VERSION 5.8 ;
BUSBITCHARS "[]" ;
DIVIDERCHAR "/" ;
UNITS DATABASE MICRONS 1000 ; END UNITS
MANUFACTURINGGRID 0.001 ;
LAYER M1 TYPE ROUTING ; DIRECTION HORIZONTAL ; PITCH 0.1 ; WIDTH 0.05 ; SPACING 0.05 ; END M1
SITE site CLASS CORE ; SIZE 1 BY 1 ; SYMMETRY Y ; END site
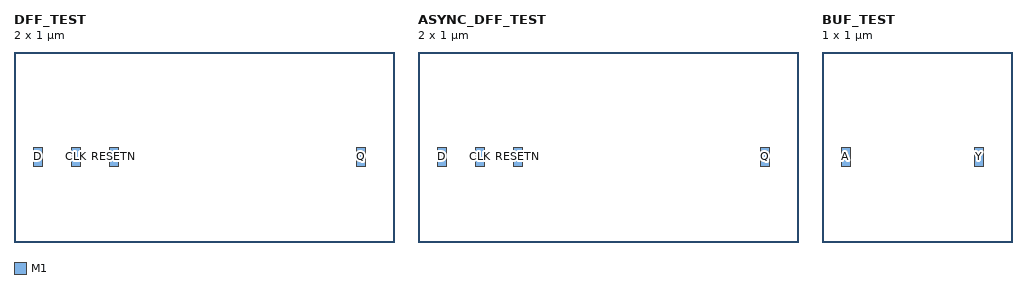
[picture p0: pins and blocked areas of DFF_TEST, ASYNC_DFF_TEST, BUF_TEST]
MACRO DFF_TEST CLASS CORE ; ORIGIN 0 0 ; SIZE 2 BY 1 ; SYMMETRY X Y ; SITE site ;
PIN D DIRECTION INPUT ; USE SIGNAL ; PORT LAYER M1 ; RECT 0.1 0.4 0.15000000000000002 0.5 ; END END D
PIN CLK DIRECTION INPUT ; USE SIGNAL ; PORT LAYER M1 ; RECT 0.3 0.4 0.35 0.5 ; END END CLK
PIN RESETN DIRECTION INPUT ; USE SIGNAL ; PORT LAYER M1 ; RECT 0.5 0.4 0.55 0.5 ; END END RESETN
PIN Q DIRECTION OUTPUT ; USE SIGNAL ; PORT LAYER M1 ; RECT 1.8 0.4 1.85 0.5 ; END END Q
END DFF_TEST
MACRO ASYNC_DFF_TEST CLASS CORE ; ORIGIN 0 0 ; SIZE 2 BY 1 ; SYMMETRY X Y ; SITE site ;
PIN D DIRECTION INPUT ; USE SIGNAL ; PORT LAYER M1 ; RECT 0.1 0.4 0.15000000000000002 0.5 ; END END D
PIN CLK DIRECTION INPUT ; USE SIGNAL ; PORT LAYER M1 ; RECT 0.3 0.4 0.35 0.5 ; END END CLK
PIN RESETN DIRECTION INPUT ; USE SIGNAL ; PORT LAYER M1 ; RECT 0.5 0.4 0.55 0.5 ; END END RESETN
PIN Q DIRECTION OUTPUT ; USE SIGNAL ; PORT LAYER M1 ; RECT 1.8 0.4 1.85 0.5 ; END END Q
END ASYNC_DFF_TEST
MACRO BUF_TEST CLASS CORE ; ORIGIN 0 0 ; SIZE 1 BY 1 ; SYMMETRY X Y ; SITE site ;
PIN A DIRECTION INPUT ; USE SIGNAL ; PORT LAYER M1 ; RECT 0.1 0.4 0.15 0.5 ; END END A
PIN Y DIRECTION OUTPUT ; USE SIGNAL ; PORT LAYER M1 ; RECT 0.8 0.4 0.85 0.5 ; END END Y
END BUF_TEST
END LIBRARY
